VERSION 5.7 ;
  NOWIREEXTENSIONATPIN ON ;
  DIVIDERCHAR "/" ;
  BUSBITCHARS "[]" ;
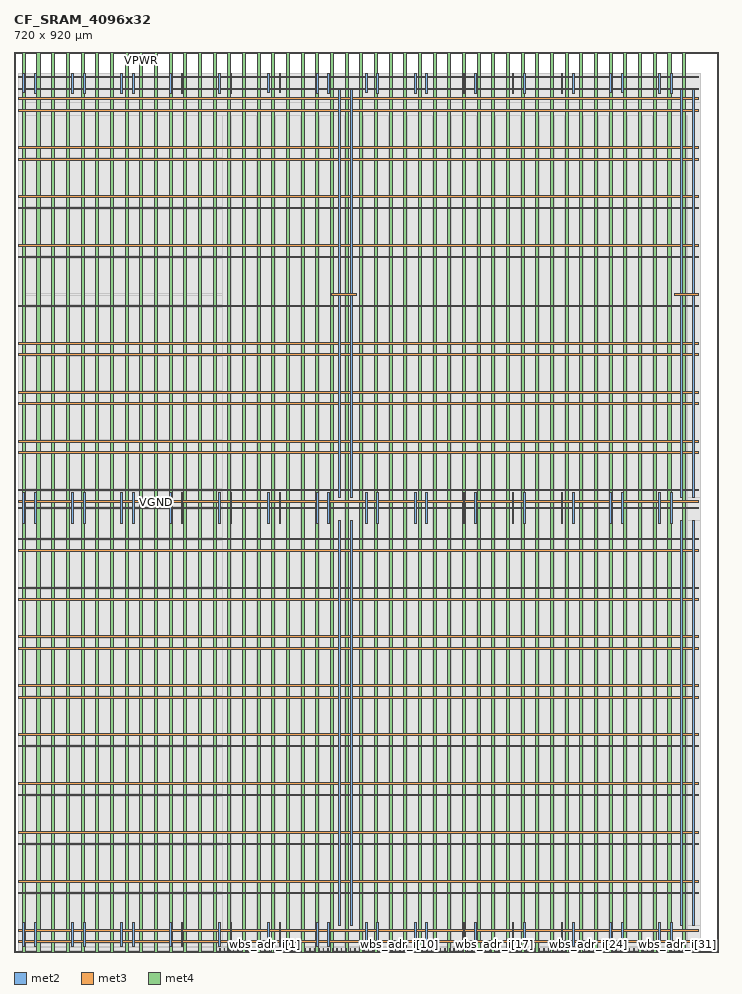
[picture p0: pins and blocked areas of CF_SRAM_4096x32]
MACRO CF_SRAM_4096x32
  CLASS BLOCK ;
  FOREIGN CF_SRAM_4096x32 ;
  ORIGIN 0.000 0.000 ;
  SIZE 720.000 BY 920.000 ;
  PIN VGND
    DIRECTION INOUT ;
    USE GROUND ;
    PORT
      LAYER met2 ;
        RECT 20.940 5.200 22.700 29.860 ;
    END
    PORT
      LAYER met2 ;
        RECT 20.940 438.010 22.700 469.860 ;
    END
    PORT
      LAYER met2 ;
        RECT 20.940 878.010 22.700 897.840 ;
    END
    PORT
      LAYER met2 ;
        RECT 70.940 5.200 72.700 29.860 ;
    END
    PORT
      LAYER met2 ;
        RECT 70.940 438.010 72.700 469.860 ;
    END
    PORT
      LAYER met2 ;
        RECT 70.940 878.010 72.700 897.840 ;
    END
    PORT
      LAYER met2 ;
        RECT 120.940 5.200 122.700 29.860 ;
    END
    PORT
      LAYER met2 ;
        RECT 120.940 438.010 122.700 469.860 ;
    END
    PORT
      LAYER met2 ;
        RECT 120.940 878.010 122.700 897.840 ;
    END
    PORT
      LAYER met2 ;
        RECT 170.940 5.200 172.700 29.860 ;
    END
    PORT
      LAYER met2 ;
        RECT 170.940 438.010 172.700 469.860 ;
    END
    PORT
      LAYER met2 ;
        RECT 170.940 878.010 172.700 897.840 ;
    END
    PORT
      LAYER met2 ;
        RECT 220.940 5.200 222.700 29.860 ;
    END
    PORT
      LAYER met2 ;
        RECT 220.940 438.010 222.700 469.860 ;
    END
    PORT
      LAYER met2 ;
        RECT 220.940 878.010 222.700 897.840 ;
    END
    PORT
      LAYER met2 ;
        RECT 270.940 5.200 272.700 29.720 ;
    END
    PORT
      LAYER met2 ;
        RECT 270.940 438.150 272.700 469.720 ;
    END
    PORT
      LAYER met2 ;
        RECT 270.940 878.150 272.700 897.840 ;
    END
    PORT
      LAYER met2 ;
        RECT 320.940 5.200 322.700 29.860 ;
    END
    PORT
      LAYER met2 ;
        RECT 320.940 438.010 322.700 469.860 ;
    END
    PORT
      LAYER met2 ;
        RECT 320.940 878.010 322.700 897.840 ;
    END
    PORT
      LAYER met2 ;
        RECT 370.940 5.200 372.700 29.860 ;
    END
    PORT
      LAYER met2 ;
        RECT 370.940 438.010 372.700 469.860 ;
    END
    PORT
      LAYER met2 ;
        RECT 370.940 878.010 372.700 897.840 ;
    END
    PORT
      LAYER met2 ;
        RECT 420.940 5.200 422.700 29.860 ;
    END
    PORT
      LAYER met2 ;
        RECT 420.940 438.010 422.700 469.860 ;
    END
    PORT
      LAYER met2 ;
        RECT 420.940 878.010 422.700 897.840 ;
    END
    PORT
      LAYER met2 ;
        RECT 470.940 5.200 472.700 29.860 ;
    END
    PORT
      LAYER met2 ;
        RECT 470.940 438.010 472.700 469.860 ;
    END
    PORT
      LAYER met2 ;
        RECT 470.940 878.010 472.700 897.840 ;
    END
    PORT
      LAYER met2 ;
        RECT 520.940 5.200 522.700 29.860 ;
    END
    PORT
      LAYER met2 ;
        RECT 520.940 438.010 522.700 469.860 ;
    END
    PORT
      LAYER met2 ;
        RECT 520.940 878.010 522.700 897.840 ;
    END
    PORT
      LAYER met2 ;
        RECT 570.940 5.200 572.700 29.860 ;
    END
    PORT
      LAYER met2 ;
        RECT 570.940 438.010 572.700 469.860 ;
    END
    PORT
      LAYER met2 ;
        RECT 570.940 878.010 572.700 897.840 ;
    END
    PORT
      LAYER met2 ;
        RECT 620.940 5.200 622.700 29.720 ;
    END
    PORT
      LAYER met2 ;
        RECT 620.940 438.150 622.700 469.720 ;
    END
    PORT
      LAYER met2 ;
        RECT 620.940 878.150 622.700 897.840 ;
    END
    PORT
      LAYER met2 ;
        RECT 670.940 5.200 672.700 29.860 ;
    END
    PORT
      LAYER met2 ;
        RECT 670.940 438.010 672.700 469.860 ;
    END
    PORT
      LAYER met2 ;
        RECT 670.940 878.010 672.700 897.840 ;
    END
    PORT
      LAYER met3 ;
        RECT 4.820 21.320 699.900 23.080 ;
    END
    PORT
      LAYER met3 ;
        RECT 4.820 71.320 699.900 73.080 ;
    END
    PORT
      LAYER met3 ;
        RECT 4.820 121.320 699.900 123.080 ;
    END
    PORT
      LAYER met3 ;
        RECT 4.820 171.320 699.900 173.080 ;
    END
    PORT
      LAYER met3 ;
        RECT 4.820 221.320 699.900 223.080 ;
    END
    PORT
      LAYER met3 ;
        RECT 4.820 271.320 699.900 273.080 ;
    END
    PORT
      LAYER met3 ;
        RECT 4.820 321.320 699.900 323.080 ;
    END
    PORT
      LAYER met3 ;
        RECT 4.820 371.320 699.900 373.080 ;
    END
    PORT
      LAYER met3 ;
        RECT 4.820 421.320 699.900 423.080 ;
    END
    PORT
      LAYER met3 ;
        RECT 4.820 471.320 699.900 473.080 ;
    END
    PORT
      LAYER met3 ;
        RECT 4.820 521.320 699.900 523.080 ;
    END
    PORT
      LAYER met3 ;
        RECT 4.820 571.320 699.900 573.080 ;
    END
    PORT
      LAYER met3 ;
        RECT 4.820 621.320 699.900 623.080 ;
    END
    PORT
      LAYER met3 ;
        RECT 4.820 721.320 699.900 723.080 ;
    END
    PORT
      LAYER met3 ;
        RECT 4.820 771.320 699.900 773.080 ;
    END
    PORT
      LAYER met3 ;
        RECT 4.820 821.320 699.900 823.080 ;
    END
    PORT
      LAYER met3 ;
        RECT 4.820 871.320 699.900 873.080 ;
    END
    PORT
      LAYER met3 ;
        RECT 324.990 671.320 349.800 673.080 ;
    END
    PORT
      LAYER met3 ;
        RECT 674.990 671.320 699.900 673.080 ;
    END
    PORT
      LAYER met4 ;
        RECT 23.510 0.000 26.610 920.000 ;
    END
    PORT
      LAYER met4 ;
        RECT 53.510 0.000 56.610 920.000 ;
    END
    PORT
      LAYER met4 ;
        RECT 83.510 0.000 86.610 920.000 ;
    END
    PORT
      LAYER met4 ;
        RECT 113.510 0.000 116.610 920.000 ;
    END
    PORT
      LAYER met4 ;
        RECT 143.510 0.000 146.610 920.000 ;
    END
    PORT
      LAYER met4 ;
        RECT 173.510 0.000 176.610 920.000 ;
    END
    PORT
      LAYER met4 ;
        RECT 203.510 0.000 206.610 920.000 ;
    END
    PORT
      LAYER met4 ;
        RECT 233.510 0.000 236.610 920.000 ;
    END
    PORT
      LAYER met4 ;
        RECT 263.510 0.000 266.610 920.000 ;
    END
    PORT
      LAYER met4 ;
        RECT 293.510 0.000 296.610 920.000 ;
    END
    PORT
      LAYER met4 ;
        RECT 323.510 0.000 326.610 920.000 ;
    END
    PORT
      LAYER met4 ;
        RECT 353.510 0.000 356.610 920.000 ;
    END
    PORT
      LAYER met4 ;
        RECT 383.510 0.000 386.610 920.000 ;
    END
    PORT
      LAYER met4 ;
        RECT 413.510 0.000 416.610 920.000 ;
    END
    PORT
      LAYER met4 ;
        RECT 443.510 0.000 446.610 920.000 ;
    END
    PORT
      LAYER met4 ;
        RECT 473.510 0.000 476.610 920.000 ;
    END
    PORT
      LAYER met4 ;
        RECT 503.510 0.000 506.610 920.000 ;
    END
    PORT
      LAYER met4 ;
        RECT 533.510 0.000 536.610 920.000 ;
    END
    PORT
      LAYER met4 ;
        RECT 563.510 0.000 566.610 920.000 ;
    END
    PORT
      LAYER met4 ;
        RECT 593.510 0.000 596.610 920.000 ;
    END
    PORT
      LAYER met4 ;
        RECT 623.510 0.000 626.610 920.000 ;
    END
    PORT
      LAYER met4 ;
        RECT 653.510 0.000 656.610 920.000 ;
    END
    PORT
      LAYER met4 ;
        RECT 683.510 0.000 686.610 920.000 ;
    END
    PORT
      LAYER met2 ;
        RECT 343.890 26.960 345.650 440.880 ;
    END
    PORT
      LAYER met2 ;
        RECT 693.490 464.880 695.250 881.520 ;
    END
    PORT
      LAYER met2 ;
        RECT 343.890 464.880 345.650 881.520 ;
    END
    PORT
      LAYER met2 ;
        RECT 693.490 26.960 695.250 440.880 ;
    END
    PORT
      LAYER met3 ;
        RECT 4.820 453.020 699.900 454.780 ;
    END
    PORT
      LAYER met3 ;
        RECT 4.820 893.660 699.900 895.420 ;
    END
  END VGND
  PIN VPWR
    DIRECTION INOUT ;
    USE POWER ;
    PORT
      LAYER met2 ;
        RECT 9.180 5.200 10.940 29.720 ;
    END
    PORT
      LAYER met2 ;
        RECT 9.180 438.150 10.940 469.720 ;
    END
    PORT
      LAYER met2 ;
        RECT 9.180 878.150 10.940 897.840 ;
    END
    PORT
      LAYER met2 ;
        RECT 59.180 5.200 60.940 29.860 ;
    END
    PORT
      LAYER met2 ;
        RECT 59.180 438.010 60.940 469.860 ;
    END
    PORT
      LAYER met2 ;
        RECT 59.180 878.010 60.940 897.840 ;
    END
    PORT
      LAYER met2 ;
        RECT 109.180 5.200 110.940 29.860 ;
    END
    PORT
      LAYER met2 ;
        RECT 109.180 438.010 110.940 469.860 ;
    END
    PORT
      LAYER met2 ;
        RECT 109.180 878.010 110.940 897.840 ;
    END
    PORT
      LAYER met2 ;
        RECT 159.180 5.200 160.940 29.860 ;
    END
    PORT
      LAYER met2 ;
        RECT 159.180 438.010 160.940 469.860 ;
    END
    PORT
      LAYER met2 ;
        RECT 159.180 878.010 160.940 897.840 ;
    END
    PORT
      LAYER met2 ;
        RECT 209.180 5.200 210.940 29.860 ;
    END
    PORT
      LAYER met2 ;
        RECT 209.180 438.010 210.940 469.860 ;
    END
    PORT
      LAYER met2 ;
        RECT 209.180 878.010 210.940 897.840 ;
    END
    PORT
      LAYER met2 ;
        RECT 259.180 5.200 260.940 29.720 ;
    END
    PORT
      LAYER met2 ;
        RECT 259.180 438.150 260.940 469.720 ;
    END
    PORT
      LAYER met2 ;
        RECT 259.180 878.150 260.940 897.840 ;
    END
    PORT
      LAYER met2 ;
        RECT 309.180 5.200 310.940 29.860 ;
    END
    PORT
      LAYER met2 ;
        RECT 309.180 438.010 310.940 469.860 ;
    END
    PORT
      LAYER met2 ;
        RECT 309.180 878.010 310.940 897.840 ;
    END
    PORT
      LAYER met2 ;
        RECT 359.180 5.200 360.940 29.720 ;
    END
    PORT
      LAYER met2 ;
        RECT 359.180 438.150 360.940 469.720 ;
    END
    PORT
      LAYER met2 ;
        RECT 359.180 878.150 360.940 897.840 ;
    END
    PORT
      LAYER met2 ;
        RECT 409.180 5.200 410.940 29.860 ;
    END
    PORT
      LAYER met2 ;
        RECT 409.180 438.010 410.940 469.860 ;
    END
    PORT
      LAYER met2 ;
        RECT 409.180 878.010 410.940 897.840 ;
    END
    PORT
      LAYER met2 ;
        RECT 459.180 5.200 460.940 29.860 ;
    END
    PORT
      LAYER met2 ;
        RECT 459.180 438.010 460.940 469.860 ;
    END
    PORT
      LAYER met2 ;
        RECT 459.180 878.010 460.940 897.840 ;
    END
    PORT
      LAYER met2 ;
        RECT 509.180 5.200 510.940 29.860 ;
    END
    PORT
      LAYER met2 ;
        RECT 509.180 438.010 510.940 469.860 ;
    END
    PORT
      LAYER met2 ;
        RECT 509.180 878.010 510.940 897.840 ;
    END
    PORT
      LAYER met2 ;
        RECT 559.180 5.200 560.940 29.860 ;
    END
    PORT
      LAYER met2 ;
        RECT 559.180 438.010 560.940 469.860 ;
    END
    PORT
      LAYER met2 ;
        RECT 559.180 878.010 560.940 897.840 ;
    END
    PORT
      LAYER met2 ;
        RECT 609.180 5.200 610.940 29.720 ;
    END
    PORT
      LAYER met2 ;
        RECT 609.180 438.150 610.940 469.720 ;
    END
    PORT
      LAYER met2 ;
        RECT 609.180 878.150 610.940 897.840 ;
    END
    PORT
      LAYER met2 ;
        RECT 659.180 5.200 660.940 29.860 ;
    END
    PORT
      LAYER met2 ;
        RECT 659.180 438.010 660.940 469.860 ;
    END
    PORT
      LAYER met2 ;
        RECT 659.180 878.010 660.940 897.840 ;
    END
    PORT
      LAYER met3 ;
        RECT 4.820 9.560 699.900 11.320 ;
    END
    PORT
      LAYER met3 ;
        RECT 4.820 59.560 699.900 61.320 ;
    END
    PORT
      LAYER met3 ;
        RECT 4.820 109.560 699.900 111.320 ;
    END
    PORT
      LAYER met3 ;
        RECT 4.820 159.560 699.900 161.320 ;
    END
    PORT
      LAYER met3 ;
        RECT 4.820 209.560 699.900 211.320 ;
    END
    PORT
      LAYER met3 ;
        RECT 4.820 259.560 699.900 261.320 ;
    END
    PORT
      LAYER met3 ;
        RECT 4.820 309.560 699.900 311.320 ;
    END
    PORT
      LAYER met3 ;
        RECT 4.820 359.560 699.900 361.320 ;
    END
    PORT
      LAYER met3 ;
        RECT 4.820 409.560 699.900 411.320 ;
    END
    PORT
      LAYER met3 ;
        RECT 4.820 459.560 699.900 461.320 ;
    END
    PORT
      LAYER met3 ;
        RECT 4.820 509.560 699.900 511.320 ;
    END
    PORT
      LAYER met3 ;
        RECT 4.820 559.560 699.900 561.320 ;
    END
    PORT
      LAYER met3 ;
        RECT 4.820 609.560 699.900 611.320 ;
    END
    PORT
      LAYER met3 ;
        RECT 4.820 659.560 699.900 661.320 ;
    END
    PORT
      LAYER met3 ;
        RECT 4.820 709.560 699.900 711.320 ;
    END
    PORT
      LAYER met3 ;
        RECT 4.820 759.560 699.900 761.320 ;
    END
    PORT
      LAYER met3 ;
        RECT 4.820 809.560 699.900 811.320 ;
    END
    PORT
      LAYER met3 ;
        RECT 4.820 859.560 699.900 861.320 ;
    END
    PORT
      LAYER met4 ;
        RECT 8.510 0.000 11.610 920.000 ;
    END
    PORT
      LAYER met4 ;
        RECT 38.510 0.000 41.610 920.000 ;
    END
    PORT
      LAYER met4 ;
        RECT 68.510 0.000 71.610 920.000 ;
    END
    PORT
      LAYER met4 ;
        RECT 98.510 0.000 101.610 920.000 ;
    END
    PORT
      LAYER met4 ;
        RECT 128.510 0.000 131.610 920.000 ;
    END
    PORT
      LAYER met4 ;
        RECT 158.510 0.000 161.610 920.000 ;
    END
    PORT
      LAYER met4 ;
        RECT 188.510 0.000 191.610 920.000 ;
    END
    PORT
      LAYER met4 ;
        RECT 218.510 0.000 221.610 920.000 ;
    END
    PORT
      LAYER met4 ;
        RECT 248.510 0.000 251.610 920.000 ;
    END
    PORT
      LAYER met4 ;
        RECT 278.510 0.000 281.610 920.000 ;
    END
    PORT
      LAYER met4 ;
        RECT 308.510 0.000 311.610 920.000 ;
    END
    PORT
      LAYER met4 ;
        RECT 338.510 0.000 341.610 920.000 ;
    END
    PORT
      LAYER met4 ;
        RECT 368.510 0.000 371.610 920.000 ;
    END
    PORT
      LAYER met4 ;
        RECT 398.510 0.000 401.610 920.000 ;
    END
    PORT
      LAYER met4 ;
        RECT 428.510 0.000 431.610 920.000 ;
    END
    PORT
      LAYER met4 ;
        RECT 458.510 0.000 461.610 920.000 ;
    END
    PORT
      LAYER met4 ;
        RECT 488.510 0.000 491.610 920.000 ;
    END
    PORT
      LAYER met4 ;
        RECT 518.510 0.000 521.610 920.000 ;
    END
    PORT
      LAYER met4 ;
        RECT 548.510 0.000 551.610 920.000 ;
    END
    PORT
      LAYER met4 ;
        RECT 578.510 0.000 581.610 920.000 ;
    END
    PORT
      LAYER met4 ;
        RECT 608.510 0.000 611.610 920.000 ;
    END
    PORT
      LAYER met4 ;
        RECT 638.510 0.000 641.610 920.000 ;
    END
    PORT
      LAYER met4 ;
        RECT 668.510 0.000 671.610 920.000 ;
    END
    PORT
      LAYER met2 ;
        RECT 331.930 26.960 333.690 440.880 ;
    END
    PORT
      LAYER met2 ;
        RECT 681.530 464.880 683.290 881.520 ;
    END
    PORT
      LAYER met2 ;
        RECT 331.930 464.880 333.690 881.520 ;
    END
    PORT
      LAYER met2 ;
        RECT 681.530 26.960 683.290 440.880 ;
    END
    PORT
      LAYER met3 ;
        RECT 4.820 881.420 699.900 883.180 ;
    END
  END VPWR
  PIN wb_clk_i
    DIRECTION INPUT ;
    USE SIGNAL ;
    ANTENNAGATEAREA 1.286700 ;
    ANTENNADIFFAREA 0.434700 ;
    PORT
      LAYER met2 ;
        RECT 210.310 0.000 210.590 4.000 ;
    END
  END wb_clk_i
  PIN wb_rst_i
    DIRECTION INPUT ;
    USE SIGNAL ;
    ANTENNAGATEAREA 0.196500 ;
    PORT
      LAYER met2 ;
        RECT 214.910 0.000 215.190 4.000 ;
    END
  END wb_rst_i
  PIN wbs_ack_o
    DIRECTION OUTPUT TRISTATE ;
    USE SIGNAL ;
    ANTENNADIFFAREA 2.673000 ;
    PORT
      LAYER met2 ;
        RECT 219.510 0.000 219.790 4.000 ;
    END
  END wbs_ack_o
  PIN wbs_adr_i[0]
    DIRECTION INPUT ;
    USE SIGNAL ;
    PORT
      LAYER met2 ;
        RECT 237.910 0.000 238.190 4.000 ;
    END
  END wbs_adr_i[0]
  PIN wbs_adr_i[10]
    DIRECTION INPUT ;
    USE SIGNAL ;
    ANTENNAGATEAREA 0.126000 ;
    PORT
      LAYER met2 ;
        RECT 394.310 0.000 394.590 4.000 ;
    END
  END wbs_adr_i[10]
  PIN wbs_adr_i[11]
    DIRECTION INPUT ;
    USE SIGNAL ;
    ANTENNAGATEAREA 0.126000 ;
    PORT
      LAYER met2 ;
        RECT 408.110 0.000 408.390 4.000 ;
    END
  END wbs_adr_i[11]
  PIN wbs_adr_i[12]
    DIRECTION INPUT ;
    USE SIGNAL ;
    ANTENNAGATEAREA 0.126000 ;
    PORT
      LAYER met2 ;
        RECT 421.910 0.000 422.190 4.000 ;
    END
  END wbs_adr_i[12]
  PIN wbs_adr_i[13]
    DIRECTION INPUT ;
    USE SIGNAL ;
    ANTENNAGATEAREA 0.126000 ;
    PORT
      LAYER met2 ;
        RECT 435.710 0.000 435.990 4.000 ;
    END
  END wbs_adr_i[13]
  PIN wbs_adr_i[14]
    DIRECTION INPUT ;
    USE SIGNAL ;
    PORT
      LAYER met2 ;
        RECT 449.510 0.000 449.790 4.000 ;
    END
  END wbs_adr_i[14]
  PIN wbs_adr_i[15]
    DIRECTION INPUT ;
    USE SIGNAL ;
    PORT
      LAYER met2 ;
        RECT 463.310 0.000 463.590 4.000 ;
    END
  END wbs_adr_i[15]
  PIN wbs_adr_i[16]
    DIRECTION INPUT ;
    USE SIGNAL ;
    PORT
      LAYER met2 ;
        RECT 477.110 0.000 477.390 4.000 ;
    END
  END wbs_adr_i[16]
  PIN wbs_adr_i[17]
    DIRECTION INPUT ;
    USE SIGNAL ;
    PORT
      LAYER met2 ;
        RECT 490.910 0.000 491.190 4.000 ;
    END
  END wbs_adr_i[17]
  PIN wbs_adr_i[18]
    DIRECTION INPUT ;
    USE SIGNAL ;
    PORT
      LAYER met2 ;
        RECT 504.710 0.000 504.990 4.000 ;
    END
  END wbs_adr_i[18]
  PIN wbs_adr_i[19]
    DIRECTION INPUT ;
    USE SIGNAL ;
    PORT
      LAYER met2 ;
        RECT 518.510 0.000 518.790 4.000 ;
    END
  END wbs_adr_i[19]
  PIN wbs_adr_i[1]
    DIRECTION INPUT ;
    USE SIGNAL ;
    PORT
      LAYER met2 ;
        RECT 256.310 0.000 256.590 4.000 ;
    END
  END wbs_adr_i[1]
  PIN wbs_adr_i[20]
    DIRECTION INPUT ;
    USE SIGNAL ;
    PORT
      LAYER met2 ;
        RECT 532.310 0.000 532.590 4.000 ;
    END
  END wbs_adr_i[20]
  PIN wbs_adr_i[21]
    DIRECTION INPUT ;
    USE SIGNAL ;
    PORT
      LAYER met2 ;
        RECT 546.110 0.000 546.390 4.000 ;
    END
  END wbs_adr_i[21]
  PIN wbs_adr_i[22]
    DIRECTION INPUT ;
    USE SIGNAL ;
    PORT
      LAYER met2 ;
        RECT 559.910 0.000 560.190 4.000 ;
    END
  END wbs_adr_i[22]
  PIN wbs_adr_i[23]
    DIRECTION INPUT ;
    USE SIGNAL ;
    PORT
      LAYER met2 ;
        RECT 573.710 0.000 573.990 4.000 ;
    END
  END wbs_adr_i[23]
  PIN wbs_adr_i[24]
    DIRECTION INPUT ;
    USE SIGNAL ;
    PORT
      LAYER met2 ;
        RECT 587.510 0.000 587.790 4.000 ;
    END
  END wbs_adr_i[24]
  PIN wbs_adr_i[25]
    DIRECTION INPUT ;
    USE SIGNAL ;
    PORT
      LAYER met2 ;
        RECT 601.310 0.000 601.590 4.000 ;
    END
  END wbs_adr_i[25]
  PIN wbs_adr_i[26]
    DIRECTION INPUT ;
    USE SIGNAL ;
    PORT
      LAYER met2 ;
        RECT 615.110 0.000 615.390 4.000 ;
    END
  END wbs_adr_i[26]
  PIN wbs_adr_i[27]
    DIRECTION INPUT ;
    USE SIGNAL ;
    PORT
      LAYER met2 ;
        RECT 628.910 0.000 629.190 4.000 ;
    END
  END wbs_adr_i[27]
  PIN wbs_adr_i[28]
    DIRECTION INPUT ;
    USE SIGNAL ;
    PORT
      LAYER met2 ;
        RECT 642.710 0.000 642.990 4.000 ;
    END
  END wbs_adr_i[28]
  PIN wbs_adr_i[29]
    DIRECTION INPUT ;
    USE SIGNAL ;
    PORT
      LAYER met2 ;
        RECT 656.510 0.000 656.790 4.000 ;
    END
  END wbs_adr_i[29]
  PIN wbs_adr_i[2]
    DIRECTION INPUT ;
    USE SIGNAL ;
    ANTENNAGATEAREA 0.126000 ;
    PORT
      LAYER met2 ;
        RECT 274.710 0.000 274.990 4.000 ;
    END
  END wbs_adr_i[2]
  PIN wbs_adr_i[30]
    DIRECTION INPUT ;
    USE SIGNAL ;
    PORT
      LAYER met2 ;
        RECT 670.310 0.000 670.590 4.000 ;
    END
  END wbs_adr_i[30]
  PIN wbs_adr_i[31]
    DIRECTION INPUT ;
    USE SIGNAL ;
    PORT
      LAYER met2 ;
        RECT 684.110 0.000 684.390 4.000 ;
    END
  END wbs_adr_i[31]
  PIN wbs_adr_i[3]
    DIRECTION INPUT ;
    USE SIGNAL ;
    ANTENNAGATEAREA 0.126000 ;
    PORT
      LAYER met2 ;
        RECT 293.110 0.000 293.390 4.000 ;
    END
  END wbs_adr_i[3]
  PIN wbs_adr_i[4]
    DIRECTION INPUT ;
    USE SIGNAL ;
    ANTENNAGATEAREA 0.126000 ;
    PORT
      LAYER met2 ;
        RECT 311.510 0.000 311.790 4.000 ;
    END
  END wbs_adr_i[4]
  PIN wbs_adr_i[5]
    DIRECTION INPUT ;
    USE SIGNAL ;
    ANTENNAGATEAREA 0.126000 ;
    PORT
      LAYER met2 ;
        RECT 325.310 0.000 325.590 4.000 ;
    END
  END wbs_adr_i[5]
  PIN wbs_adr_i[6]
    DIRECTION INPUT ;
    USE SIGNAL ;
    ANTENNAGATEAREA 0.126000 ;
    PORT
      LAYER met2 ;
        RECT 339.110 0.000 339.390 4.000 ;
    END
  END wbs_adr_i[6]
  PIN wbs_adr_i[7]
    DIRECTION INPUT ;
    USE SIGNAL ;
    ANTENNAGATEAREA 0.126000 ;
    PORT
      LAYER met2 ;
        RECT 352.910 0.000 353.190 4.000 ;
    END
  END wbs_adr_i[7]
  PIN wbs_adr_i[8]
    DIRECTION INPUT ;
    USE SIGNAL ;
    ANTENNAGATEAREA 0.126000 ;
    PORT
      LAYER met2 ;
        RECT 366.710 0.000 366.990 4.000 ;
    END
  END wbs_adr_i[8]
  PIN wbs_adr_i[9]
    DIRECTION INPUT ;
    USE SIGNAL ;
    ANTENNAGATEAREA 0.126000 ;
    PORT
      LAYER met2 ;
        RECT 380.510 0.000 380.790 4.000 ;
    END
  END wbs_adr_i[9]
  PIN wbs_cyc_i
    DIRECTION INPUT ;
    USE SIGNAL ;
    ANTENNAGATEAREA 0.213000 ;
    PORT
      LAYER met2 ;
        RECT 224.110 0.000 224.390 4.000 ;
    END
  END wbs_cyc_i
  PIN wbs_dat_i[0]
    DIRECTION INPUT ;
    USE SIGNAL ;
    ANTENNAGATEAREA 0.126000 ;
    PORT
      LAYER met2 ;
        RECT 242.510 0.000 242.790 4.000 ;
    END
  END wbs_dat_i[0]
  PIN wbs_dat_i[10]
    DIRECTION INPUT ;
    USE SIGNAL ;
    ANTENNAGATEAREA 0.126000 ;
    PORT
      LAYER met2 ;
        RECT 398.910 0.000 399.190 4.000 ;
    END
  END wbs_dat_i[10]
  PIN wbs_dat_i[11]
    DIRECTION INPUT ;
    USE SIGNAL ;
    ANTENNAGATEAREA 0.126000 ;
    PORT
      LAYER met2 ;
        RECT 412.710 0.000 412.990 4.000 ;
    END
  END wbs_dat_i[11]
  PIN wbs_dat_i[12]
    DIRECTION INPUT ;
    USE SIGNAL ;
    ANTENNAGATEAREA 0.126000 ;
    PORT
      LAYER met2 ;
        RECT 426.510 0.000 426.790 4.000 ;
    END
  END wbs_dat_i[12]
  PIN wbs_dat_i[13]
    DIRECTION INPUT ;
    USE SIGNAL ;
    ANTENNAGATEAREA 0.126000 ;
    PORT
      LAYER met2 ;
        RECT 440.310 0.000 440.590 4.000 ;
    END
  END wbs_dat_i[13]
  PIN wbs_dat_i[14]
    DIRECTION INPUT ;
    USE SIGNAL ;
    ANTENNAGATEAREA 0.126000 ;
    PORT
      LAYER met2 ;
        RECT 454.110 0.000 454.390 4.000 ;
    END
  END wbs_dat_i[14]
  PIN wbs_dat_i[15]
    DIRECTION INPUT ;
    USE SIGNAL ;
    ANTENNAGATEAREA 0.126000 ;
    PORT
      LAYER met2 ;
        RECT 467.910 0.000 468.190 4.000 ;
    END
  END wbs_dat_i[15]
  PIN wbs_dat_i[16]
    DIRECTION INPUT ;
    USE SIGNAL ;
    ANTENNAGATEAREA 0.126000 ;
    PORT
      LAYER met2 ;
        RECT 481.710 0.000 481.990 4.000 ;
    END
  END wbs_dat_i[16]
  PIN wbs_dat_i[17]
    DIRECTION INPUT ;
    USE SIGNAL ;
    ANTENNAGATEAREA 0.126000 ;
    PORT
      LAYER met2 ;
        RECT 495.510 0.000 495.790 4.000 ;
    END
  END wbs_dat_i[17]
  PIN wbs_dat_i[18]
    DIRECTION INPUT ;
    USE SIGNAL ;
    ANTENNAGATEAREA 0.126000 ;
    PORT
      LAYER met2 ;
        RECT 509.310 0.000 509.590 4.000 ;
    END
  END wbs_dat_i[18]
  PIN wbs_dat_i[19]
    DIRECTION INPUT ;
    USE SIGNAL ;
    ANTENNAGATEAREA 0.126000 ;
    PORT
      LAYER met2 ;
        RECT 523.110 0.000 523.390 4.000 ;
    END
  END wbs_dat_i[19]
  PIN wbs_dat_i[1]
    DIRECTION INPUT ;
    USE SIGNAL ;
    ANTENNAGATEAREA 0.126000 ;
    PORT
      LAYER met2 ;
        RECT 260.910 0.000 261.190 4.000 ;
    END
  END wbs_dat_i[1]
  PIN wbs_dat_i[20]
    DIRECTION INPUT ;
    USE SIGNAL ;
    ANTENNAGATEAREA 0.126000 ;
    PORT
      LAYER met2 ;
        RECT 536.910 0.000 537.190 4.000 ;
    END
  END wbs_dat_i[20]
  PIN wbs_dat_i[21]
    DIRECTION INPUT ;
    USE SIGNAL ;
    ANTENNAGATEAREA 0.126000 ;
    PORT
      LAYER met2 ;
        RECT 550.710 0.000 550.990 4.000 ;
    END
  END wbs_dat_i[21]
  PIN wbs_dat_i[22]
    DIRECTION INPUT ;
    USE SIGNAL ;
    ANTENNAGATEAREA 0.126000 ;
    PORT
      LAYER met2 ;
        RECT 564.510 0.000 564.790 4.000 ;
    END
  END wbs_dat_i[22]
  PIN wbs_dat_i[23]
    DIRECTION INPUT ;
    USE SIGNAL ;
    ANTENNAGATEAREA 0.126000 ;
    PORT
      LAYER met2 ;
        RECT 578.310 0.000 578.590 4.000 ;
    END
  END wbs_dat_i[23]
  PIN wbs_dat_i[24]
    DIRECTION INPUT ;
    USE SIGNAL ;
    ANTENNAGATEAREA 0.126000 ;
    PORT
      LAYER met2 ;
        RECT 592.110 0.000 592.390 4.000 ;
    END
  END wbs_dat_i[24]
  PIN wbs_dat_i[25]
    DIRECTION INPUT ;
    USE SIGNAL ;
    ANTENNAGATEAREA 0.126000 ;
    PORT
      LAYER met2 ;
        RECT 605.910 0.000 606.190 4.000 ;
    END
  END wbs_dat_i[25]
  PIN wbs_dat_i[26]
    DIRECTION INPUT ;
    USE SIGNAL ;
    ANTENNAGATEAREA 0.126000 ;
    PORT
      LAYER met2 ;
        RECT 619.710 0.000 619.990 4.000 ;
    END
  END wbs_dat_i[26]
  PIN wbs_dat_i[27]
    DIRECTION INPUT ;
    USE SIGNAL ;
    ANTENNAGATEAREA 0.126000 ;
    PORT
      LAYER met2 ;
        RECT 633.510 0.000 633.790 4.000 ;
    END
  END wbs_dat_i[27]
  PIN wbs_dat_i[28]
    DIRECTION INPUT ;
    USE SIGNAL ;
    ANTENNAGATEAREA 0.126000 ;
    PORT
      LAYER met2 ;
        RECT 647.310 0.000 647.590 4.000 ;
    END
  END wbs_dat_i[28]
  PIN wbs_dat_i[29]
    DIRECTION INPUT ;
    USE SIGNAL ;
    ANTENNAGATEAREA 0.126000 ;
    PORT
      LAYER met2 ;
        RECT 661.110 0.000 661.390 4.000 ;
    END
  END wbs_dat_i[29]
  PIN wbs_dat_i[2]
    DIRECTION INPUT ;
    USE SIGNAL ;
    ANTENNAGATEAREA 0.126000 ;
    PORT
      LAYER met2 ;
        RECT 279.310 0.000 279.590 4.000 ;
    END
  END wbs_dat_i[2]
  PIN wbs_dat_i[30]
    DIRECTION INPUT ;
    USE SIGNAL ;
    ANTENNAGATEAREA 0.126000 ;
    PORT
      LAYER met2 ;
        RECT 674.910 0.000 675.190 4.000 ;
    END
  END wbs_dat_i[30]
  PIN wbs_dat_i[31]
    DIRECTION INPUT ;
    USE SIGNAL ;
    ANTENNAGATEAREA 0.126000 ;
    PORT
      LAYER met2 ;
        RECT 688.710 0.000 688.990 4.000 ;
    END
  END wbs_dat_i[31]
  PIN wbs_dat_i[3]
    DIRECTION INPUT ;
    USE SIGNAL ;
    ANTENNAGATEAREA 0.126000 ;
    PORT
      LAYER met2 ;
        RECT 297.710 0.000 297.990 4.000 ;
    END
  END wbs_dat_i[3]
  PIN wbs_dat_i[4]
    DIRECTION INPUT ;
    USE SIGNAL ;
    ANTENNAGATEAREA 0.126000 ;
    PORT
      LAYER met2 ;
        RECT 316.110 0.000 316.390 4.000 ;
    END
  END wbs_dat_i[4]
  PIN wbs_dat_i[5]
    DIRECTION INPUT ;
    USE SIGNAL ;
    ANTENNAGATEAREA 0.126000 ;
    PORT
      LAYER met2 ;
        RECT 329.910 0.000 330.190 4.000 ;
    END
  END wbs_dat_i[5]
  PIN wbs_dat_i[6]
    DIRECTION INPUT ;
    USE SIGNAL ;
    ANTENNAGATEAREA 0.126000 ;
    PORT
      LAYER met2 ;
        RECT 343.710 0.000 343.990 4.000 ;
    END
  END wbs_dat_i[6]
  PIN wbs_dat_i[7]
    DIRECTION INPUT ;
    USE SIGNAL ;
    ANTENNAGATEAREA 0.126000 ;
    PORT
      LAYER met2 ;
        RECT 357.510 0.000 357.790 4.000 ;
    END
  END wbs_dat_i[7]
  PIN wbs_dat_i[8]
    DIRECTION INPUT ;
    USE SIGNAL ;
    ANTENNAGATEAREA 0.126000 ;
    PORT
      LAYER met2 ;
        RECT 371.310 0.000 371.590 4.000 ;
    END
  END wbs_dat_i[8]
  PIN wbs_dat_i[9]
    DIRECTION INPUT ;
    USE SIGNAL ;
    ANTENNAGATEAREA 0.126000 ;
    PORT
      LAYER met2 ;
        RECT 385.110 0.000 385.390 4.000 ;
    END
  END wbs_dat_i[9]
  PIN wbs_dat_o[0]
    DIRECTION OUTPUT TRISTATE ;
    USE SIGNAL ;
    ANTENNADIFFAREA 2.673000 ;
    PORT
      LAYER met2 ;
        RECT 247.110 0.000 247.390 4.000 ;
    END
  END wbs_dat_o[0]
  PIN wbs_dat_o[10]
    DIRECTION OUTPUT TRISTATE ;
    USE SIGNAL ;
    ANTENNADIFFAREA 2.673000 ;
    PORT
      LAYER met2 ;
        RECT 403.510 0.000 403.790 4.000 ;
    END
  END wbs_dat_o[10]
  PIN wbs_dat_o[11]
    DIRECTION OUTPUT TRISTATE ;
    USE SIGNAL ;
    ANTENNADIFFAREA 2.673000 ;
    PORT
      LAYER met2 ;
        RECT 417.310 0.000 417.590 4.000 ;
    END
  END wbs_dat_o[11]
  PIN wbs_dat_o[12]
    DIRECTION OUTPUT TRISTATE ;
    USE SIGNAL ;
    ANTENNADIFFAREA 2.673000 ;
    PORT
      LAYER met2 ;
        RECT 431.110 0.000 431.390 4.000 ;
    END
  END wbs_dat_o[12]
  PIN wbs_dat_o[13]
    DIRECTION OUTPUT TRISTATE ;
    USE SIGNAL ;
    ANTENNADIFFAREA 2.673000 ;
    PORT
      LAYER met2 ;
        RECT 444.910 0.000 445.190 4.000 ;
    END
  END wbs_dat_o[13]
  PIN wbs_dat_o[14]
    DIRECTION OUTPUT TRISTATE ;
    USE SIGNAL ;
    ANTENNADIFFAREA 2.673000 ;
    PORT
      LAYER met2 ;
        RECT 458.710 0.000 458.990 4.000 ;
    END
  END wbs_dat_o[14]
  PIN wbs_dat_o[15]
    DIRECTION OUTPUT TRISTATE ;
    USE SIGNAL ;
    ANTENNADIFFAREA 2.673000 ;
    PORT
      LAYER met2 ;
        RECT 472.510 0.000 472.790 4.000 ;
    END
  END wbs_dat_o[15]
  PIN wbs_dat_o[16]
    DIRECTION OUTPUT TRISTATE ;
    USE SIGNAL ;
    ANTENNADIFFAREA 2.673000 ;
    PORT
      LAYER met2 ;
        RECT 486.310 0.000 486.590 4.000 ;
    END
  END wbs_dat_o[16]
  PIN wbs_dat_o[17]
    DIRECTION OUTPUT TRISTATE ;
    USE SIGNAL ;
    ANTENNADIFFAREA 2.673000 ;
    PORT
      LAYER met2 ;
        RECT 500.110 0.000 500.390 4.000 ;
    END
  END wbs_dat_o[17]
  PIN wbs_dat_o[18]
    DIRECTION OUTPUT TRISTATE ;
    USE SIGNAL ;
    ANTENNADIFFAREA 2.673000 ;
    PORT
      LAYER met2 ;
        RECT 513.910 0.000 514.190 4.000 ;
    END
  END wbs_dat_o[18]
  PIN wbs_dat_o[19]
    DIRECTION OUTPUT TRISTATE ;
    USE SIGNAL ;
    ANTENNADIFFAREA 2.673000 ;
    PORT
      LAYER met2 ;
        RECT 527.710 0.000 527.990 4.000 ;
    END
  END wbs_dat_o[19]
  PIN wbs_dat_o[1]
    DIRECTION OUTPUT TRISTATE ;
    USE SIGNAL ;
    ANTENNADIFFAREA 2.673000 ;
    PORT
      LAYER met2 ;
        RECT 265.510 0.000 265.790 4.000 ;
    END
  END wbs_dat_o[1]
  PIN wbs_dat_o[20]
    DIRECTION OUTPUT TRISTATE ;
    USE SIGNAL ;
    ANTENNADIFFAREA 2.673000 ;
    PORT
      LAYER met2 ;
        RECT 541.510 0.000 541.790 4.000 ;
    END
  END wbs_dat_o[20]
  PIN wbs_dat_o[21]
    DIRECTION OUTPUT TRISTATE ;
    USE SIGNAL ;
    ANTENNADIFFAREA 2.673000 ;
    PORT
      LAYER met2 ;
        RECT 555.310 0.000 555.590 4.000 ;
    END
  END wbs_dat_o[21]
  PIN wbs_dat_o[22]
    DIRECTION OUTPUT TRISTATE ;
    USE SIGNAL ;
    ANTENNADIFFAREA 2.673000 ;
    PORT
      LAYER met2 ;
        RECT 569.110 0.000 569.390 4.000 ;
    END
  END wbs_dat_o[22]
  PIN wbs_dat_o[23]
    DIRECTION OUTPUT TRISTATE ;
    USE SIGNAL ;
    ANTENNADIFFAREA 2.673000 ;
    PORT
      LAYER met2 ;
        RECT 582.910 0.000 583.190 4.000 ;
    END
  END wbs_dat_o[23]
  PIN wbs_dat_o[24]
    DIRECTION OUTPUT TRISTATE ;
    USE SIGNAL ;
    ANTENNADIFFAREA 2.673000 ;
    PORT
      LAYER met2 ;
        RECT 596.710 0.000 596.990 4.000 ;
    END
  END wbs_dat_o[24]
  PIN wbs_dat_o[25]
    DIRECTION OUTPUT TRISTATE ;
    USE SIGNAL ;
    ANTENNADIFFAREA 2.673000 ;
    PORT
      LAYER met2 ;
        RECT 610.510 0.000 610.790 4.000 ;
    END
  END wbs_dat_o[25]
  PIN wbs_dat_o[26]
    DIRECTION OUTPUT TRISTATE ;
    USE SIGNAL ;
    ANTENNADIFFAREA 2.673000 ;
    PORT
      LAYER met2 ;
        RECT 624.310 0.000 624.590 4.000 ;
    END
  END wbs_dat_o[26]
  PIN wbs_dat_o[27]
    DIRECTION OUTPUT TRISTATE ;
    USE SIGNAL ;
    ANTENNADIFFAREA 2.673000 ;
    PORT
      LAYER met2 ;
        RECT 638.110 0.000 638.390 4.000 ;
    END
  END wbs_dat_o[27]
  PIN wbs_dat_o[28]
    DIRECTION OUTPUT TRISTATE ;
    USE SIGNAL ;
    ANTENNADIFFAREA 2.673000 ;
    PORT
      LAYER met2 ;
        RECT 651.910 0.000 652.190 4.000 ;
    END
  END wbs_dat_o[28]
  PIN wbs_dat_o[29]
    DIRECTION OUTPUT TRISTATE ;
    USE SIGNAL ;
    ANTENNADIFFAREA 2.673000 ;
    PORT
      LAYER met2 ;
        RECT 665.710 0.000 665.990 4.000 ;
    END
  END wbs_dat_o[29]
  PIN wbs_dat_o[2]
    DIRECTION OUTPUT TRISTATE ;
    USE SIGNAL ;
    ANTENNADIFFAREA 2.673000 ;
    PORT
      LAYER met2 ;
        RECT 283.910 0.000 284.190 4.000 ;
    END
  END wbs_dat_o[2]
  PIN wbs_dat_o[30]
    DIRECTION OUTPUT TRISTATE ;
    USE SIGNAL ;
    ANTENNADIFFAREA 2.673000 ;
    PORT
      LAYER met2 ;
        RECT 679.510 0.000 679.790 4.000 ;
    END
  END wbs_dat_o[30]
  PIN wbs_dat_o[31]
    DIRECTION OUTPUT TRISTATE ;
    USE SIGNAL ;
    ANTENNADIFFAREA 2.673000 ;
    PORT
      LAYER met2 ;
        RECT 693.310 0.000 693.590 4.000 ;
    END
  END wbs_dat_o[31]
  PIN wbs_dat_o[3]
    DIRECTION OUTPUT TRISTATE ;
    USE SIGNAL ;
    ANTENNADIFFAREA 2.673000 ;
    PORT
      LAYER met2 ;
        RECT 302.310 0.000 302.590 4.000 ;
    END
  END wbs_dat_o[3]
  PIN wbs_dat_o[4]
    DIRECTION OUTPUT TRISTATE ;
    USE SIGNAL ;
    ANTENNADIFFAREA 2.673000 ;
    PORT
      LAYER met2 ;
        RECT 320.710 0.000 320.990 4.000 ;
    END
  END wbs_dat_o[4]
  PIN wbs_dat_o[5]
    DIRECTION OUTPUT TRISTATE ;
    USE SIGNAL ;
    ANTENNADIFFAREA 2.673000 ;
    PORT
      LAYER met2 ;
        RECT 334.510 0.000 334.790 4.000 ;
    END
  END wbs_dat_o[5]
  PIN wbs_dat_o[6]
    DIRECTION OUTPUT TRISTATE ;
    USE SIGNAL ;
    ANTENNADIFFAREA 2.673000 ;
    PORT
      LAYER met2 ;
        RECT 348.310 0.000 348.590 4.000 ;
    END
  END wbs_dat_o[6]
  PIN wbs_dat_o[7]
    DIRECTION OUTPUT TRISTATE ;
    USE SIGNAL ;
    ANTENNADIFFAREA 2.673000 ;
    PORT
      LAYER met2 ;
        RECT 362.110 0.000 362.390 4.000 ;
    END
  END wbs_dat_o[7]
  PIN wbs_dat_o[8]
    DIRECTION OUTPUT TRISTATE ;
    USE SIGNAL ;
    ANTENNADIFFAREA 2.673000 ;
    PORT
      LAYER met2 ;
        RECT 375.910 0.000 376.190 4.000 ;
    END
  END wbs_dat_o[8]
  PIN wbs_dat_o[9]
    DIRECTION OUTPUT TRISTATE ;
    USE SIGNAL ;
    ANTENNADIFFAREA 2.673000 ;
    PORT
      LAYER met2 ;
        RECT 389.710 0.000 389.990 4.000 ;
    END
  END wbs_dat_o[9]
  PIN wbs_sel_i[0]
    DIRECTION INPUT ;
    USE SIGNAL ;
    ANTENNAGATEAREA 0.126000 ;
    PORT
      LAYER met2 ;
        RECT 251.710 0.000 251.990 4.000 ;
    END
  END wbs_sel_i[0]
  PIN wbs_sel_i[1]
    DIRECTION INPUT ;
    USE SIGNAL ;
    ANTENNAGATEAREA 0.126000 ;
    PORT
      LAYER met2 ;
        RECT 270.110 0.000 270.390 4.000 ;
    END
  END wbs_sel_i[1]
  PIN wbs_sel_i[2]
    DIRECTION INPUT ;
    USE SIGNAL ;
    ANTENNAGATEAREA 0.126000 ;
    PORT
      LAYER met2 ;
        RECT 288.510 0.000 288.790 4.000 ;
    END
  END wbs_sel_i[2]
  PIN wbs_sel_i[3]
    DIRECTION INPUT ;
    USE SIGNAL ;
    ANTENNAGATEAREA 0.126000 ;
    PORT
      LAYER met2 ;
        RECT 306.910 0.000 307.190 4.000 ;
    END
  END wbs_sel_i[3]
  PIN wbs_stb_i
    DIRECTION INPUT ;
    USE SIGNAL ;
    ANTENNAGATEAREA 0.213000 ;
    PORT
      LAYER met2 ;
        RECT 228.710 0.000 228.990 4.000 ;
    END
  END wbs_stb_i
  PIN wbs_we_i
    DIRECTION INPUT ;
    USE SIGNAL ;
    ANTENNAGATEAREA 0.126000 ;
    PORT
      LAYER met2 ;
        RECT 233.310 0.000 233.590 4.000 ;
    END
  END wbs_we_i
  OBS
      LAYER li1 ;
        RECT 5.060 5.355 699.660 897.685 ;
      LAYER met1 ;
        RECT 5.060 1.740 701.430 897.840 ;
      LAYER met2 ;
        RECT 10.100 470.140 331.650 868.690 ;
        RECT 10.100 470.000 20.660 470.140 ;
        RECT 11.220 437.870 20.660 470.000 ;
        RECT 10.100 437.730 20.660 437.870 ;
        RECT 22.980 437.730 58.900 470.140 ;
        RECT 61.220 437.730 70.660 470.140 ;
        RECT 72.980 437.730 108.900 470.140 ;
        RECT 111.220 437.730 120.660 470.140 ;
        RECT 122.980 437.730 158.900 470.140 ;
        RECT 161.220 437.730 170.660 470.140 ;
        RECT 172.980 437.730 208.900 470.140 ;
        RECT 211.220 437.730 220.660 470.140 ;
        RECT 222.980 470.000 308.900 470.140 ;
        RECT 222.980 437.870 258.900 470.000 ;
        RECT 261.220 437.870 270.660 470.000 ;
        RECT 272.980 437.870 308.900 470.000 ;
        RECT 222.980 437.730 308.900 437.870 ;
        RECT 311.220 437.730 320.660 470.140 ;
        RECT 322.980 464.600 331.650 470.140 ;
        RECT 333.970 464.600 343.610 868.690 ;
        RECT 345.930 470.140 681.250 868.690 ;
        RECT 345.930 470.000 370.660 470.140 ;
        RECT 345.930 464.600 358.900 470.000 ;
        RECT 322.980 441.160 358.900 464.600 ;
        RECT 322.980 437.730 331.650 441.160 ;
        RECT 10.100 30.140 331.650 437.730 ;
        RECT 10.100 30.000 20.660 30.140 ;
        RECT 11.220 4.920 20.660 30.000 ;
        RECT 22.980 4.920 58.900 30.140 ;
        RECT 61.220 4.920 70.660 30.140 ;
        RECT 72.980 4.920 108.900 30.140 ;
        RECT 111.220 4.920 120.660 30.140 ;
        RECT 122.980 4.920 158.900 30.140 ;
        RECT 161.220 4.920 170.660 30.140 ;
        RECT 172.980 4.920 208.900 30.140 ;
        RECT 211.220 4.920 220.660 30.140 ;
        RECT 222.980 30.000 308.900 30.140 ;
        RECT 222.980 4.920 258.900 30.000 ;
        RECT 261.220 4.920 270.660 30.000 ;
        RECT 272.980 4.920 308.900 30.000 ;
        RECT 311.220 4.920 320.660 30.140 ;
        RECT 322.980 26.680 331.650 30.140 ;
        RECT 333.970 26.680 343.610 441.160 ;
        RECT 345.930 437.870 358.900 441.160 ;
        RECT 361.220 437.870 370.660 470.000 ;
        RECT 345.930 437.730 370.660 437.870 ;
        RECT 372.980 437.730 408.900 470.140 ;
        RECT 411.220 437.730 420.660 470.140 ;
        RECT 422.980 437.730 458.900 470.140 ;
        RECT 461.220 437.730 470.660 470.140 ;
        RECT 472.980 437.730 508.900 470.140 ;
        RECT 511.220 437.730 520.660 470.140 ;
        RECT 522.980 437.730 558.900 470.140 ;
        RECT 561.220 437.730 570.660 470.140 ;
        RECT 572.980 470.000 658.900 470.140 ;
        RECT 572.980 437.870 608.900 470.000 ;
        RECT 611.220 437.870 620.660 470.000 ;
        RECT 622.980 437.870 658.900 470.000 ;
        RECT 572.980 437.730 658.900 437.870 ;
        RECT 661.220 437.730 670.660 470.140 ;
        RECT 672.980 464.600 681.250 470.140 ;
        RECT 683.570 464.600 693.210 868.690 ;
        RECT 695.530 464.600 701.400 868.690 ;
        RECT 672.980 441.160 701.400 464.600 ;
        RECT 672.980 437.730 681.250 441.160 ;
        RECT 345.930 30.140 681.250 437.730 ;
        RECT 345.930 30.000 370.660 30.140 ;
        RECT 345.930 26.680 358.900 30.000 ;
        RECT 322.980 4.920 358.900 26.680 ;
        RECT 361.220 4.920 370.660 30.000 ;
        RECT 372.980 4.920 408.900 30.140 ;
        RECT 411.220 4.920 420.660 30.140 ;
        RECT 422.980 4.920 458.900 30.140 ;
        RECT 461.220 4.920 470.660 30.140 ;
        RECT 472.980 4.920 508.900 30.140 ;
        RECT 511.220 4.920 520.660 30.140 ;
        RECT 522.980 4.920 558.900 30.140 ;
        RECT 561.220 4.920 570.660 30.140 ;
        RECT 572.980 30.000 658.900 30.140 ;
        RECT 572.980 4.920 608.900 30.000 ;
        RECT 611.220 4.920 620.660 30.000 ;
        RECT 622.980 4.920 658.900 30.000 ;
        RECT 661.220 4.920 670.660 30.140 ;
        RECT 672.980 26.680 681.250 30.140 ;
        RECT 683.570 26.680 693.210 441.160 ;
        RECT 695.530 26.680 701.400 441.160 ;
        RECT 672.980 4.920 701.400 26.680 ;
        RECT 10.100 4.280 701.400 4.920 ;
        RECT 10.100 1.710 210.030 4.280 ;
        RECT 210.870 1.710 214.630 4.280 ;
        RECT 215.470 1.710 219.230 4.280 ;
        RECT 220.070 1.710 223.830 4.280 ;
        RECT 224.670 1.710 228.430 4.280 ;
        RECT 229.270 1.710 233.030 4.280 ;
        RECT 233.870 1.710 237.630 4.280 ;
        RECT 238.470 1.710 242.230 4.280 ;
        RECT 243.070 1.710 246.830 4.280 ;
        RECT 247.670 1.710 251.430 4.280 ;
        RECT 252.270 1.710 256.030 4.280 ;
        RECT 256.870 1.710 260.630 4.280 ;
        RECT 261.470 1.710 265.230 4.280 ;
        RECT 266.070 1.710 269.830 4.280 ;
        RECT 270.670 1.710 274.430 4.280 ;
        RECT 275.270 1.710 279.030 4.280 ;
        RECT 279.870 1.710 283.630 4.280 ;
        RECT 284.470 1.710 288.230 4.280 ;
        RECT 289.070 1.710 292.830 4.280 ;
        RECT 293.670 1.710 297.430 4.280 ;
        RECT 298.270 1.710 302.030 4.280 ;
        RECT 302.870 1.710 306.630 4.280 ;
        RECT 307.470 1.710 311.230 4.280 ;
        RECT 312.070 1.710 315.830 4.280 ;
        RECT 316.670 1.710 320.430 4.280 ;
        RECT 321.270 1.710 325.030 4.280 ;
        RECT 325.870 1.710 329.630 4.280 ;
        RECT 330.470 1.710 334.230 4.280 ;
        RECT 335.070 1.710 338.830 4.280 ;
        RECT 339.670 1.710 343.430 4.280 ;
        RECT 344.270 1.710 348.030 4.280 ;
        RECT 348.870 1.710 352.630 4.280 ;
        RECT 353.470 1.710 357.230 4.280 ;
        RECT 358.070 1.710 361.830 4.280 ;
        RECT 362.670 1.710 366.430 4.280 ;
        RECT 367.270 1.710 371.030 4.280 ;
        RECT 371.870 1.710 375.630 4.280 ;
        RECT 376.470 1.710 380.230 4.280 ;
        RECT 381.070 1.710 384.830 4.280 ;
        RECT 385.670 1.710 389.430 4.280 ;
        RECT 390.270 1.710 394.030 4.280 ;
        RECT 394.870 1.710 398.630 4.280 ;
        RECT 399.470 1.710 403.230 4.280 ;
        RECT 404.070 1.710 407.830 4.280 ;
        RECT 408.670 1.710 412.430 4.280 ;
        RECT 413.270 1.710 417.030 4.280 ;
        RECT 417.870 1.710 421.630 4.280 ;
        RECT 422.470 1.710 426.230 4.280 ;
        RECT 427.070 1.710 430.830 4.280 ;
        RECT 431.670 1.710 435.430 4.280 ;
        RECT 436.270 1.710 440.030 4.280 ;
        RECT 440.870 1.710 444.630 4.280 ;
        RECT 445.470 1.710 449.230 4.280 ;
        RECT 450.070 1.710 453.830 4.280 ;
        RECT 454.670 1.710 458.430 4.280 ;
        RECT 459.270 1.710 463.030 4.280 ;
        RECT 463.870 1.710 467.630 4.280 ;
        RECT 468.470 1.710 472.230 4.280 ;
        RECT 473.070 1.710 476.830 4.280 ;
        RECT 477.670 1.710 481.430 4.280 ;
        RECT 482.270 1.710 486.030 4.280 ;
        RECT 486.870 1.710 490.630 4.280 ;
        RECT 491.470 1.710 495.230 4.280 ;
        RECT 496.070 1.710 499.830 4.280 ;
        RECT 500.670 1.710 504.430 4.280 ;
        RECT 505.270 1.710 509.030 4.280 ;
        RECT 509.870 1.710 513.630 4.280 ;
        RECT 514.470 1.710 518.230 4.280 ;
        RECT 519.070 1.710 522.830 4.280 ;
        RECT 523.670 1.710 527.430 4.280 ;
        RECT 528.270 1.710 532.030 4.280 ;
        RECT 532.870 1.710 536.630 4.280 ;
        RECT 537.470 1.710 541.230 4.280 ;
        RECT 542.070 1.710 545.830 4.280 ;
        RECT 546.670 1.710 550.430 4.280 ;
        RECT 551.270 1.710 555.030 4.280 ;
        RECT 555.870 1.710 559.630 4.280 ;
        RECT 560.470 1.710 564.230 4.280 ;
        RECT 565.070 1.710 568.830 4.280 ;
        RECT 569.670 1.710 573.430 4.280 ;
        RECT 574.270 1.710 578.030 4.280 ;
        RECT 578.870 1.710 582.630 4.280 ;
        RECT 583.470 1.710 587.230 4.280 ;
        RECT 588.070 1.710 591.830 4.280 ;
        RECT 592.670 1.710 596.430 4.280 ;
        RECT 597.270 1.710 601.030 4.280 ;
        RECT 601.870 1.710 605.630 4.280 ;
        RECT 606.470 1.710 610.230 4.280 ;
        RECT 611.070 1.710 614.830 4.280 ;
        RECT 615.670 1.710 619.430 4.280 ;
        RECT 620.270 1.710 624.030 4.280 ;
        RECT 624.870 1.710 628.630 4.280 ;
        RECT 629.470 1.710 633.230 4.280 ;
        RECT 634.070 1.710 637.830 4.280 ;
        RECT 638.670 1.710 642.430 4.280 ;
        RECT 643.270 1.710 647.030 4.280 ;
        RECT 647.870 1.710 651.630 4.280 ;
        RECT 652.470 1.710 656.230 4.280 ;
        RECT 657.070 1.710 660.830 4.280 ;
        RECT 661.670 1.710 665.430 4.280 ;
        RECT 666.270 1.710 670.030 4.280 ;
        RECT 670.870 1.710 674.630 4.280 ;
        RECT 675.470 1.710 679.230 4.280 ;
        RECT 680.070 1.710 683.830 4.280 ;
        RECT 684.670 1.710 688.430 4.280 ;
        RECT 689.270 1.710 693.030 4.280 ;
        RECT 693.870 1.710 701.400 4.280 ;
      LAYER met3 ;
        RECT 10.100 823.480 688.810 854.585 ;
        RECT 10.100 811.720 688.810 820.920 ;
        RECT 10.100 773.480 688.810 809.160 ;
        RECT 10.100 761.720 688.810 770.920 ;
        RECT 10.100 723.480 688.810 759.160 ;
        RECT 10.100 711.720 688.810 720.920 ;
        RECT 10.100 673.480 688.810 709.160 ;
        RECT 10.100 670.920 324.590 673.480 ;
        RECT 350.200 670.920 674.590 673.480 ;
        RECT 10.100 661.720 688.810 670.920 ;
        RECT 10.100 623.480 688.810 659.160 ;
        RECT 10.100 611.720 688.810 620.920 ;
        RECT 10.100 573.480 688.810 609.160 ;
        RECT 10.100 561.720 688.810 570.920 ;
        RECT 10.100 523.480 688.810 559.160 ;
        RECT 10.100 511.720 688.810 520.920 ;
        RECT 10.100 473.480 688.810 509.160 ;
        RECT 10.100 461.720 688.810 470.920 ;
        RECT 10.100 455.180 688.810 459.160 ;
        RECT 10.100 423.480 688.810 452.620 ;
        RECT 10.100 411.720 688.810 420.920 ;
        RECT 10.100 373.480 688.810 409.160 ;
        RECT 10.100 361.720 688.810 370.920 ;
        RECT 10.100 323.480 688.810 359.160 ;
        RECT 10.100 311.720 688.810 320.920 ;
        RECT 10.100 273.480 688.810 309.160 ;
        RECT 10.100 261.720 688.810 270.920 ;
        RECT 10.100 223.480 688.810 259.160 ;
        RECT 10.100 211.720 688.810 220.920 ;
        RECT 10.100 173.480 688.810 209.160 ;
        RECT 10.100 161.720 688.810 170.920 ;
        RECT 10.100 123.480 688.810 159.160 ;
        RECT 10.100 111.720 688.810 120.920 ;
        RECT 10.100 73.480 688.810 109.160 ;
        RECT 10.100 61.720 688.810 70.920 ;
        RECT 10.100 23.480 688.810 59.160 ;
        RECT 10.100 11.720 688.810 20.920 ;
        RECT 10.100 5.615 688.810 9.160 ;
      LAYER met4 ;
        RECT 212.815 5.615 218.110 854.585 ;
        RECT 222.010 5.615 233.110 854.585 ;
        RECT 237.010 5.615 248.110 854.585 ;
        RECT 252.010 5.615 263.110 854.585 ;
        RECT 267.010 5.615 278.110 854.585 ;
        RECT 282.010 5.615 293.110 854.585 ;
        RECT 297.010 5.615 308.110 854.585 ;
        RECT 312.010 5.615 323.110 854.585 ;
        RECT 327.010 5.615 338.110 854.585 ;
        RECT 342.010 5.615 353.110 854.585 ;
        RECT 357.010 5.615 368.110 854.585 ;
        RECT 372.010 5.615 383.110 854.585 ;
        RECT 387.010 5.615 398.110 854.585 ;
        RECT 402.010 5.615 413.110 854.585 ;
        RECT 417.010 5.615 428.110 854.585 ;
        RECT 432.010 5.615 443.110 854.585 ;
        RECT 447.010 5.615 458.110 854.585 ;
        RECT 462.010 5.615 473.110 854.585 ;
        RECT 477.010 5.615 488.110 854.585 ;
        RECT 492.010 5.615 503.110 854.585 ;
        RECT 507.010 5.615 518.110 854.585 ;
        RECT 522.010 5.615 533.110 854.585 ;
        RECT 537.010 5.615 548.110 854.585 ;
        RECT 552.010 5.615 563.110 854.585 ;
        RECT 567.010 5.615 578.110 854.585 ;
        RECT 582.010 5.615 593.110 854.585 ;
        RECT 597.010 5.615 608.110 854.585 ;
        RECT 612.010 5.615 623.110 854.585 ;
        RECT 627.010 5.615 638.110 854.585 ;
        RECT 642.010 5.615 653.110 854.585 ;
        RECT 657.010 5.615 668.110 854.585 ;
        RECT 672.010 5.615 683.110 854.585 ;
        RECT 687.010 5.615 688.785 854.585 ;
  END
END CF_SRAM_4096x32
END LIBRARY

